VERSION 5.4 ;
NAMESCASESENSITIVE ON ;
BUSBITCHARS "[]" ;
DIVIDERCHAR "/" ;
UNITS
  DATABASE MICRONS 2000 ;
END UNITS
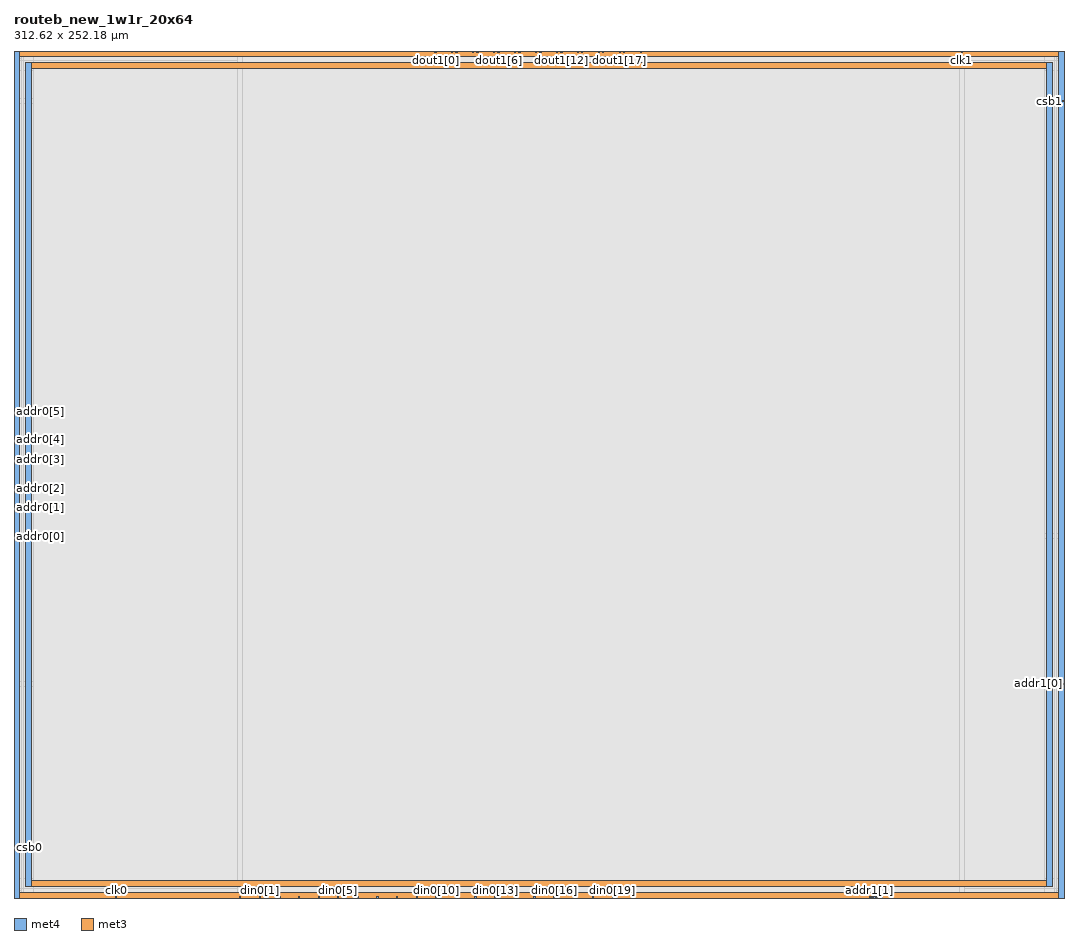
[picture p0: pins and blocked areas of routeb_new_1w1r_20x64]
MACRO routeb_new_1w1r_20x64
   CLASS BLOCK ;
   SIZE 312.62 BY 252.18 ;
   SYMMETRY X Y R90 ;
   PIN din0[0]
      DIRECTION INPUT ;
      PORT
         LAYER met4 ;
         RECT  67.16 0.0 67.54 0.38 ;
      END
   END din0[0]
   PIN din0[1]
      DIRECTION INPUT ;
      PORT
         LAYER met4 ;
         RECT  73.0 0.0 73.38 0.38 ;
      END
   END din0[1]
   PIN din0[2]
      DIRECTION INPUT ;
      PORT
         LAYER met4 ;
         RECT  78.84 0.0 79.22 0.38 ;
      END
   END din0[2]
   PIN din0[3]
      DIRECTION INPUT ;
      PORT
         LAYER met4 ;
         RECT  84.68 0.0 85.06 0.38 ;
      END
   END din0[3]
   PIN din0[4]
      DIRECTION INPUT ;
      PORT
         LAYER met4 ;
         RECT  90.52 0.0 90.9 0.38 ;
      END
   END din0[4]
   PIN din0[5]
      DIRECTION INPUT ;
      PORT
         LAYER met4 ;
         RECT  96.36 0.0 96.74 0.38 ;
      END
   END din0[5]
   PIN din0[6]
      DIRECTION INPUT ;
      PORT
         LAYER met4 ;
         RECT  102.2 0.0 102.58 0.38 ;
      END
   END din0[6]
   PIN din0[7]
      DIRECTION INPUT ;
      PORT
         LAYER met4 ;
         RECT  108.04 0.0 108.42 0.38 ;
      END
   END din0[7]
   PIN din0[8]
      DIRECTION INPUT ;
      PORT
         LAYER met4 ;
         RECT  113.88 0.0 114.26 0.38 ;
      END
   END din0[8]
   PIN din0[9]
      DIRECTION INPUT ;
      PORT
         LAYER met4 ;
         RECT  119.72 0.0 120.1 0.38 ;
      END
   END din0[9]
   PIN din0[10]
      DIRECTION INPUT ;
      PORT
         LAYER met4 ;
         RECT  125.56 0.0 125.94 0.38 ;
      END
   END din0[10]
   PIN din0[11]
      DIRECTION INPUT ;
      PORT
         LAYER met4 ;
         RECT  131.4 0.0 131.78 0.38 ;
      END
   END din0[11]
   PIN din0[12]
      DIRECTION INPUT ;
      PORT
         LAYER met4 ;
         RECT  137.24 0.0 137.62 0.38 ;
      END
   END din0[12]
   PIN din0[13]
      DIRECTION INPUT ;
      PORT
         LAYER met4 ;
         RECT  143.08 0.0 143.46 0.38 ;
      END
   END din0[13]
   PIN din0[14]
      DIRECTION INPUT ;
      PORT
         LAYER met4 ;
         RECT  148.92 0.0 149.3 0.38 ;
      END
   END din0[14]
   PIN din0[15]
      DIRECTION INPUT ;
      PORT
         LAYER met4 ;
         RECT  154.76 0.0 155.14 0.38 ;
      END
   END din0[15]
   PIN din0[16]
      DIRECTION INPUT ;
      PORT
         LAYER met4 ;
         RECT  160.6 0.0 160.98 0.38 ;
      END
   END din0[16]
   PIN din0[17]
      DIRECTION INPUT ;
      PORT
         LAYER met4 ;
         RECT  166.44 0.0 166.82 0.38 ;
      END
   END din0[17]
   PIN din0[18]
      DIRECTION INPUT ;
      PORT
         LAYER met4 ;
         RECT  172.28 0.0 172.66 0.38 ;
      END
   END din0[18]
   PIN din0[19]
      DIRECTION INPUT ;
      PORT
         LAYER met4 ;
         RECT  178.12 0.0 178.5 0.38 ;
      END
   END din0[19]
   PIN addr0[0]
      DIRECTION INPUT ;
      PORT
         LAYER met3 ;
         RECT  0.0 107.58 0.38 107.96 ;
      END
   END addr0[0]
   PIN addr0[1]
      DIRECTION INPUT ;
      PORT
         LAYER met3 ;
         RECT  0.0 116.08 0.38 116.46 ;
      END
   END addr0[1]
   PIN addr0[2]
      DIRECTION INPUT ;
      PORT
         LAYER met3 ;
         RECT  0.0 121.72 0.38 122.1 ;
      END
   END addr0[2]
   PIN addr0[3]
      DIRECTION INPUT ;
      PORT
         LAYER met3 ;
         RECT  0.0 130.22 0.38 130.6 ;
      END
   END addr0[3]
   PIN addr0[4]
      DIRECTION INPUT ;
      PORT
         LAYER met3 ;
         RECT  0.0 136.275 0.38 136.655 ;
      END
   END addr0[4]
   PIN addr0[5]
      DIRECTION INPUT ;
      PORT
         LAYER met3 ;
         RECT  0.0 144.675 0.38 145.055 ;
      END
   END addr0[5]
   PIN addr1[0]
      DIRECTION INPUT ;
      PORT
         LAYER met3 ;
         RECT  312.24 63.54 312.62 63.92 ;
      END
   END addr1[0]
   PIN addr1[1]
      DIRECTION INPUT ;
      PORT
         LAYER met4 ;
         RECT  254.635 0.0 255.015 0.38 ;
      END
   END addr1[1]
   PIN addr1[2]
      DIRECTION INPUT ;
      PORT
         LAYER met4 ;
         RECT  258.3 0.0 258.68 0.38 ;
      END
   END addr1[2]
   PIN addr1[3]
      DIRECTION INPUT ;
      PORT
         LAYER met4 ;
         RECT  255.325 0.0 255.705 0.38 ;
      END
   END addr1[3]
   PIN addr1[4]
      DIRECTION INPUT ;
      PORT
         LAYER met4 ;
         RECT  256.015 0.0 256.395 0.38 ;
      END
   END addr1[4]
   PIN addr1[5]
      DIRECTION INPUT ;
      PORT
         LAYER met4 ;
         RECT  256.76 0.0 257.14 0.38 ;
      END
   END addr1[5]
   PIN csb0
      DIRECTION INPUT ;
      PORT
         LAYER met3 ;
         RECT  0.0 14.87 0.38 15.25 ;
      END
   END csb0
   PIN csb1
      DIRECTION INPUT ;
      PORT
         LAYER met3 ;
         RECT  312.24 237.075 312.62 237.455 ;
      END
   END csb1
   PIN clk0
      DIRECTION INPUT ;
      PORT
         LAYER met4 ;
         RECT  30.26 0.0 30.64 0.38 ;
      END
   END clk0
   PIN clk1
      DIRECTION INPUT ;
      PORT
         LAYER met4 ;
         RECT  281.98 251.8 282.36 252.18 ;
      END
   END clk1
   PIN dout1[0]
      DIRECTION OUTPUT ;
      PORT
         LAYER met4 ;
         RECT  125.345 251.8 125.725 252.18 ;
      END
   END dout1[0]
   PIN dout1[1]
      DIRECTION OUTPUT ;
      PORT
         LAYER met4 ;
         RECT  130.315 251.8 130.695 252.18 ;
      END
   END dout1[1]
   PIN dout1[2]
      DIRECTION OUTPUT ;
      PORT
         LAYER met4 ;
         RECT  131.585 251.8 131.965 252.18 ;
      END
   END dout1[2]
   PIN dout1[3]
      DIRECTION OUTPUT ;
      PORT
         LAYER met4 ;
         RECT  136.555 251.8 136.935 252.18 ;
      END
   END dout1[3]
   PIN dout1[4]
      DIRECTION OUTPUT ;
      PORT
         LAYER met4 ;
         RECT  137.825 251.8 138.205 252.18 ;
      END
   END dout1[4]
   PIN dout1[5]
      DIRECTION OUTPUT ;
      PORT
         LAYER met4 ;
         RECT  142.795 251.8 143.175 252.18 ;
      END
   END dout1[5]
   PIN dout1[6]
      DIRECTION OUTPUT ;
      PORT
         LAYER met4 ;
         RECT  144.065 251.8 144.445 252.18 ;
      END
   END dout1[6]
   PIN dout1[7]
      DIRECTION OUTPUT ;
      PORT
         LAYER met4 ;
         RECT  149.035 251.8 149.415 252.18 ;
      END
   END dout1[7]
   PIN dout1[8]
      DIRECTION OUTPUT ;
      PORT
         LAYER met4 ;
         RECT  150.305 251.8 150.685 252.18 ;
      END
   END dout1[8]
   PIN dout1[9]
      DIRECTION OUTPUT ;
      PORT
         LAYER met4 ;
         RECT  155.275 251.8 155.655 252.18 ;
      END
   END dout1[9]
   PIN dout1[10]
      DIRECTION OUTPUT ;
      PORT
         LAYER met4 ;
         RECT  156.545 251.8 156.925 252.18 ;
      END
   END dout1[10]
   PIN dout1[11]
      DIRECTION OUTPUT ;
      PORT
         LAYER met4 ;
         RECT  161.515 251.8 161.895 252.18 ;
      END
   END dout1[11]
   PIN dout1[12]
      DIRECTION OUTPUT ;
      PORT
         LAYER met4 ;
         RECT  162.785 251.8 163.165 252.18 ;
      END
   END dout1[12]
   PIN dout1[13]
      DIRECTION OUTPUT ;
      PORT
         LAYER met4 ;
         RECT  167.755 251.8 168.135 252.18 ;
      END
   END dout1[13]
   PIN dout1[14]
      DIRECTION OUTPUT ;
      PORT
         LAYER met4 ;
         RECT  169.025 251.8 169.405 252.18 ;
      END
   END dout1[14]
   PIN dout1[15]
      DIRECTION OUTPUT ;
      PORT
         LAYER met4 ;
         RECT  173.995 251.8 174.375 252.18 ;
      END
   END dout1[15]
   PIN dout1[16]
      DIRECTION OUTPUT ;
      PORT
         LAYER met4 ;
         RECT  175.265 251.8 175.645 252.18 ;
      END
   END dout1[16]
   PIN dout1[17]
      DIRECTION OUTPUT ;
      PORT
         LAYER met4 ;
         RECT  180.235 251.8 180.615 252.18 ;
      END
   END dout1[17]
   PIN dout1[18]
      DIRECTION OUTPUT ;
      PORT
         LAYER met4 ;
         RECT  181.505 251.8 181.885 252.18 ;
      END
   END dout1[18]
   PIN dout1[19]
      DIRECTION OUTPUT ;
      PORT
         LAYER met4 ;
         RECT  186.475 251.8 186.855 252.18 ;
      END
   END dout1[19]
   PIN vccd1
      DIRECTION INOUT ;
      USE POWER ; 
      SHAPE ABUTMENT ; 
      PORT
         LAYER met4 ;
         RECT  0.0 0.0 1.74 252.18 ;
         LAYER met3 ;
         RECT  0.0 0.0 312.62 1.74 ;
         LAYER met4 ;
         RECT  310.88 0.0 312.62 252.18 ;
         LAYER met3 ;
         RECT  0.0 250.44 312.62 252.18 ;
      END
   END vccd1
   PIN vssd1
      DIRECTION INOUT ;
      USE GROUND ; 
      SHAPE ABUTMENT ; 
      PORT
         LAYER met3 ;
         RECT  3.48 3.48 309.14 5.22 ;
         LAYER met4 ;
         RECT  307.4 3.48 309.14 248.7 ;
         LAYER met4 ;
         RECT  3.48 3.48 5.22 248.7 ;
         LAYER met3 ;
         RECT  3.48 246.96 309.14 248.7 ;
      END
   END vssd1
   OBS
   LAYER  met1 ;
      RECT  0.62 0.62 312.0 251.56 ;
   LAYER  met2 ;
      RECT  0.62 0.62 312.0 251.56 ;
   LAYER  met3 ;
      RECT  0.98 106.98 312.0 108.56 ;
      RECT  0.62 108.56 0.98 115.48 ;
      RECT  0.62 117.06 0.98 121.12 ;
      RECT  0.62 122.7 0.98 129.62 ;
      RECT  0.62 131.2 0.98 135.675 ;
      RECT  0.62 137.255 0.98 144.075 ;
      RECT  0.98 62.94 311.64 64.52 ;
      RECT  0.98 64.52 311.64 106.98 ;
      RECT  311.64 64.52 312.0 106.98 ;
      RECT  0.62 15.85 0.98 106.98 ;
      RECT  0.98 108.56 311.64 236.475 ;
      RECT  0.98 236.475 311.64 238.055 ;
      RECT  311.64 108.56 312.0 236.475 ;
      RECT  311.64 2.34 312.0 62.94 ;
      RECT  0.62 2.34 0.98 14.27 ;
      RECT  0.62 145.655 0.98 249.84 ;
      RECT  311.64 238.055 312.0 249.84 ;
      RECT  0.98 2.34 2.88 2.88 ;
      RECT  0.98 2.88 2.88 5.82 ;
      RECT  0.98 5.82 2.88 62.94 ;
      RECT  2.88 2.34 309.74 2.88 ;
      RECT  2.88 5.82 309.74 62.94 ;
      RECT  309.74 2.34 311.64 2.88 ;
      RECT  309.74 2.88 311.64 5.82 ;
      RECT  309.74 5.82 311.64 62.94 ;
      RECT  0.98 238.055 2.88 246.36 ;
      RECT  0.98 246.36 2.88 249.3 ;
      RECT  0.98 249.3 2.88 249.84 ;
      RECT  2.88 238.055 309.74 246.36 ;
      RECT  2.88 249.3 309.74 249.84 ;
      RECT  309.74 238.055 311.64 246.36 ;
      RECT  309.74 246.36 311.64 249.3 ;
      RECT  309.74 249.3 311.64 249.84 ;
   LAYER  met4 ;
      RECT  66.56 0.98 68.14 251.56 ;
      RECT  68.14 0.62 72.4 0.98 ;
      RECT  73.98 0.62 78.24 0.98 ;
      RECT  79.82 0.62 84.08 0.98 ;
      RECT  85.66 0.62 89.92 0.98 ;
      RECT  91.5 0.62 95.76 0.98 ;
      RECT  97.34 0.62 101.6 0.98 ;
      RECT  103.18 0.62 107.44 0.98 ;
      RECT  109.02 0.62 113.28 0.98 ;
      RECT  114.86 0.62 119.12 0.98 ;
      RECT  120.7 0.62 124.96 0.98 ;
      RECT  126.54 0.62 130.8 0.98 ;
      RECT  132.38 0.62 136.64 0.98 ;
      RECT  138.22 0.62 142.48 0.98 ;
      RECT  144.06 0.62 148.32 0.98 ;
      RECT  149.9 0.62 154.16 0.98 ;
      RECT  155.74 0.62 160.0 0.98 ;
      RECT  161.58 0.62 165.84 0.98 ;
      RECT  167.42 0.62 171.68 0.98 ;
      RECT  173.26 0.62 177.52 0.98 ;
      RECT  179.1 0.62 254.035 0.98 ;
      RECT  31.24 0.62 66.56 0.98 ;
      RECT  68.14 0.98 281.38 251.2 ;
      RECT  281.38 0.98 282.96 251.2 ;
      RECT  68.14 251.2 124.745 251.56 ;
      RECT  126.325 251.2 129.715 251.56 ;
      RECT  132.565 251.2 135.955 251.56 ;
      RECT  138.805 251.2 142.195 251.56 ;
      RECT  145.045 251.2 148.435 251.56 ;
      RECT  151.285 251.2 154.675 251.56 ;
      RECT  157.525 251.2 160.915 251.56 ;
      RECT  163.765 251.2 167.155 251.56 ;
      RECT  170.005 251.2 173.395 251.56 ;
      RECT  176.245 251.2 179.635 251.56 ;
      RECT  182.485 251.2 185.875 251.56 ;
      RECT  187.455 251.2 281.38 251.56 ;
      RECT  2.34 0.62 29.66 0.98 ;
      RECT  259.28 0.62 310.28 0.98 ;
      RECT  282.96 251.2 310.28 251.56 ;
      RECT  282.96 0.98 306.8 2.88 ;
      RECT  282.96 2.88 306.8 249.3 ;
      RECT  282.96 249.3 306.8 251.2 ;
      RECT  306.8 0.98 309.74 2.88 ;
      RECT  306.8 249.3 309.74 251.2 ;
      RECT  309.74 0.98 310.28 2.88 ;
      RECT  309.74 2.88 310.28 249.3 ;
      RECT  309.74 249.3 310.28 251.2 ;
      RECT  2.34 0.98 2.88 2.88 ;
      RECT  2.34 2.88 2.88 249.3 ;
      RECT  2.34 249.3 2.88 251.56 ;
      RECT  2.88 0.98 5.82 2.88 ;
      RECT  2.88 249.3 5.82 251.56 ;
      RECT  5.82 0.98 66.56 2.88 ;
      RECT  5.82 2.88 66.56 249.3 ;
      RECT  5.82 249.3 66.56 251.56 ;
   END
END    routeb_new_1w1r_20x64
END    LIBRARY
